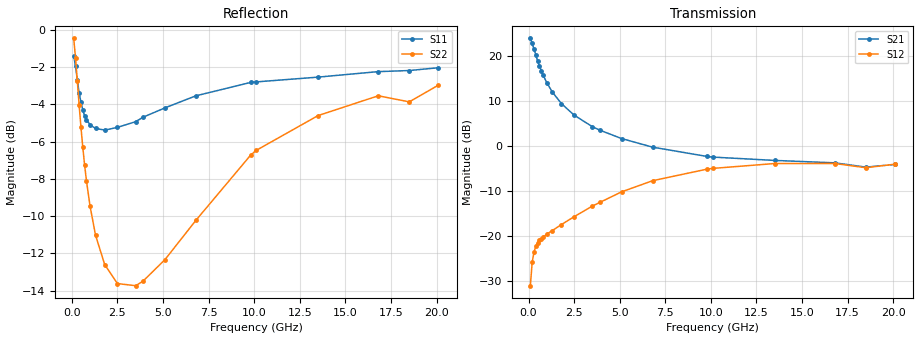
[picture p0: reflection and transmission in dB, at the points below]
!  Infineon Technologies AG
! BFR380L3 , PF131585-7, No.6, Th 09.10.01, soldered on pcb-board, measured with PP GSG850
!  Vce=2.5 V,  Ic=5.0 mA
! Common Emitter S-Parameters:  15. November 2001
#  GHz  S  MA  R  50
! f  S11  S21  S12  S22
! GHz  Mag  Ang  Mag  Ang  Mag  Ang  Mag  Ang
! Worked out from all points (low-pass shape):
!   201 points, 100 MHz to 20.1 GHz, reference 50 ohm
!   highest |S21| = 23.84 dB at 100 MHz (marker M1); lowest = -4.7 dB at 18.5 GHz (marker M2)
!   |S21| within 3 dB of the highest: start of sweep to 347.8 MHz
!   lowest |S11| = -5.4 dB at 1.8 GHz (marker M3), VSWR 3.33, Z = 15 - j1.02 ohm
!   |S11| at or under -10 dB: nowhere
!   |S22| runs from -13.9 to -0.5 dB; largest |S21 - S12| = 16
!   S11 on the Smith chart (normalised r, x): 100 MHz: 1.21, -3.56; 400 MHz: 0.36, -0.90; 1 GHz: 0.31, -0.27; 3.9 GHz: 0.29, +0.33; 9.8 GHz: 0.38, +1.12; 20.1 GHz: 0.96, +2.53
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0.1  0.8509 -28.4  15.55 161.0  0.0283 73.1  0.9484 -17.6
0.2  0.7985 -53.8  13.73 144.8  0.05115 63.1  0.8426 -32.1
0.3  0.7335 -75.1  11.84 132.3  0.06681 54.6  0.7276 -43.1
0.4  0.6771 -91.7  10.17 122.6  0.077 48.9  0.6271 -51.1
0.5  0.6389 -105.7  8.797 115.0  0.08413 45.4  0.5473 -57.1
0.6  0.61 -116.7  7.689 109.0  0.08978 43.2  0.4838 -61.6
0.7  0.5882 -126.1  6.815 103.9  0.09401 41.9  0.4337 -65.2
0.8  0.5746 -133.9  6.094 99.6  0.09797 41.5  0.3937 -68.2
1  0.5553 -146.5  5.027 92.6  0.1051 41.3  0.3359 -72.8
1.3  0.544 -160.6  3.971 84.2  0.1154 42.7  0.2811 -78.4
1.8  0.5381 -177.4  2.949 73.1  0.1344 45.5  0.2346 -86.3
2.5  0.5474 165.7  2.194 60.4  0.1645 48.4  0.2086 -98.1
3.5  0.567 147.2  1.635 45.3  0.2155 49.7  0.2059 -116.1
3.9  0.5827 141.2  1.498 40.2  0.2363 49.4  0.2117 -124.9
5.1  0.6173 124.5  1.208 26.1  0.3098 45.4  0.2417 -147.4
6.8  0.6651 104.9  0.9694 10.7  0.4118 36.4  0.3082 -178.5
9.799999  0.7224 79.8  0.7644 -6.5  0.554 16.1  0.4609 140.3
10.1  0.7248 77.5  0.7525 -7.9  0.5637 14.0  0.4746 136.8
13.5  0.7465 59.8  0.6911 -21.4  0.6383 -8.4  0.5887 103.0
16.8  0.7723 47.3  0.6497 -32.5  0.6388 -25.2  0.6652 79.2
18.5  0.7775 45.5  0.5822 -40.0  0.5737 -33.8  0.6408 73.1
20.1  0.7912 38.6  0.6242 -43.5  0.6284 -39.0  0.7105 62.0
